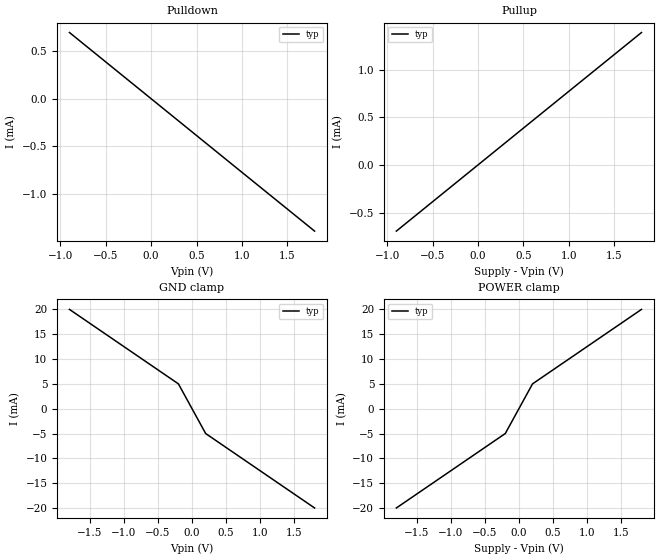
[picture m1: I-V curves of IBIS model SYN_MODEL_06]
[IBIS Ver] 7.2
[File Name] SYN_MODEL_06.ibs
[File Rev] 1.0
[Date] 07-NOV-2025
[Source] Synthetic IBIS models for testing
[Disclaimer] For educational and testing use only
[Component] SYN_COMP_06
[Manufacturer] OpenSim Labs
[Package]
R_pkg = 0.524
L_pkg = 5.04e-09
C_pkg = 4.4e-12
[Pin] signal_name model_name R_pin L_pin C_pin
1   IO1   SYN_MODEL_06   0.0   0.0   0.0
2   VCC   POWER   0.0   0.0   0.0
3   GND   GND   0.0   0.0   0.0
| Models and submodels in the file (1): SYN_MODEL_06 (i/o)
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[Model] SYN_MODEL_06
Model_type i/o
Polarity   Non-Inverting
Enable   Active-High
Vinh   0.99
Vinl   0.45
Vref   0.9
C_comp   4.02pF
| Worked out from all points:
|   GND clamp passes 1 mA (typ) near -0.04 V on its own axis
|   POWER clamp passes 1 mA (typ) near -0.04 V on its own axis
| IV tables
[Pullup]
|V (V)   I (A)
-900mV    -695uA     NA         NA
0V        0A         NA         NA
900mV     695uA      NA         NA
1.8V      1.389mA    NA         NA
[Pulldown]
|V (V)   I (A)
-900mV    695uA      NA         NA
0V        0A         NA         NA
900mV     -695uA     NA         NA
1.8V      -1.389mA   NA         NA
[GND Clamp]
|V (V)   I (A)
-1.8V     20mA       NA         NA
-200mV    5mA        NA         NA
0V        0A         NA         NA
200mV     -5mA       NA         NA
1.8V      -20mA      NA         NA
[POWER Clamp]
|V (V)   I (A)
-1.8V     -20mA      NA         NA
-200mV    -5mA       NA         NA
0V        0A         NA         NA
200mV     5mA        NA         NA
1.8V      20mA       NA         NA
| Dynamic behavior
[Voltage Time]
R_fixture 50.0
V_fixture 1.800
| Rising Waveform
|t (s)   V (V)
 0.000e+00   0.000000
 6.875e-11   0.540000
 1.375e-10   1.080000
 2.062e-10   1.530000
 2.750e-10   1.800000
[Voltage Time]
R_fixture 50.0
V_fixture 1.800
| Falling Waveform
|t (s)   V (V)
 0.000e+00   1.800000
 6.127e-11   1.260000
 1.225e-10   0.720000
 1.838e-10   0.270000
 2.451e-10   0.000000
